VERSION 5.8 ;
BUSBITCHARS "[]" ;
DIVIDERCHAR "/" ;
UNITS
    DATABASE MICRONS 1000 ;
END UNITS

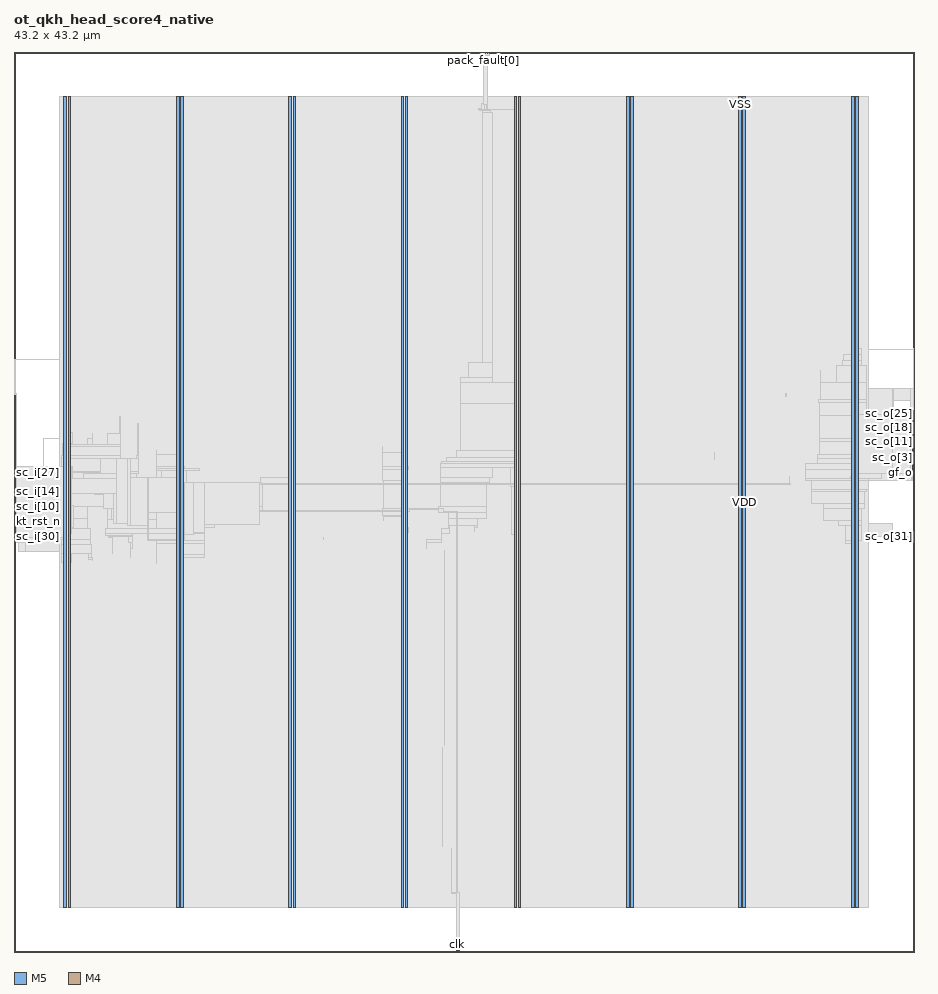
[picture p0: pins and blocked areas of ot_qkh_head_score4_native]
MACRO ot_qkh_head_score4_native
  FOREIGN ot_qkh_head_score4_native 0 0 ;
  CLASS BLOCK ;
  SIZE 43.2 BY 43.2 ;
  PIN clk
    DIRECTION INPUT ;
    USE SIGNAL ;
    PORT
      LAYER M5 ;
        RECT  21.264 0 21.288 0.084 ;
    END
  END clk
  PIN gf_i
    DIRECTION INPUT ;
    USE SIGNAL ;
    PORT
      LAYER M4 ;
        RECT  0 20.208 0.084 20.232 ;
    END
  END gf_i
  PIN gf_o
    DIRECTION OUTPUT ;
    USE SIGNAL ;
    PORT
      LAYER M4 ;
        RECT  43.116 22.992 43.2 23.016 ;
    END
  END gf_o
  PIN kt_rst_n
    DIRECTION OUTPUT ;
    USE SIGNAL ;
    PORT
      LAYER M4 ;
        RECT  0 20.304 0.084 20.328 ;
    END
  END kt_rst_n
  PIN pack_fault[0]
    DIRECTION INPUT ;
    USE SIGNAL ;
    PORT
      LAYER M5 ;
        RECT  22.512 43.116 22.536 43.2 ;
    END
  END pack_fault[0]
  PIN pack_fault[1]
    DIRECTION INPUT ;
    USE SIGNAL ;
    PORT
      LAYER M5 ;
        RECT  22.608 43.116 22.632 43.2 ;
    END
  END pack_fault[1]
  PIN pack_fault[2]
    DIRECTION INPUT ;
    USE SIGNAL ;
    PORT
      LAYER M5 ;
        RECT  22.704 43.116 22.728 43.2 ;
    END
  END pack_fault[2]
  PIN pack_fault[3]
    DIRECTION INPUT ;
    USE SIGNAL ;
    PORT
      LAYER M5 ;
        RECT  22.8 43.116 22.824 43.2 ;
    END
  END pack_fault[3]
  PIN rst_n
    DIRECTION INPUT ;
    USE SIGNAL ;
    PORT
      LAYER M5 ;
        RECT  21.36 0 21.384 0.084 ;
    END
  END rst_n
  PIN sc_i[0]
    DIRECTION INPUT ;
    USE SIGNAL ;
    PORT
      LAYER M4 ;
        RECT  0 20.4 0.084 20.424 ;
    END
  END sc_i[0]
  PIN sc_i[10]
    DIRECTION INPUT ;
    USE SIGNAL ;
    PORT
      LAYER M4 ;
        RECT  0 21.36 0.084 21.384 ;
    END
  END sc_i[10]
  PIN sc_i[11]
    DIRECTION INPUT ;
    USE SIGNAL ;
    PORT
      LAYER M4 ;
        RECT  0 21.456 0.084 21.48 ;
    END
  END sc_i[11]
  PIN sc_i[12]
    DIRECTION INPUT ;
    USE SIGNAL ;
    PORT
      LAYER M4 ;
        RECT  0 21.552 0.084 21.576 ;
    END
  END sc_i[12]
  PIN sc_i[13]
    DIRECTION INPUT ;
    USE SIGNAL ;
    PORT
      LAYER M4 ;
        RECT  0 21.648 0.084 21.672 ;
    END
  END sc_i[13]
  PIN sc_i[14]
    DIRECTION INPUT ;
    USE SIGNAL ;
    PORT
      LAYER M4 ;
        RECT  0 21.744 0.084 21.768 ;
    END
  END sc_i[14]
  PIN sc_i[15]
    DIRECTION INPUT ;
    USE SIGNAL ;
    PORT
      LAYER M4 ;
        RECT  0 21.84 0.084 21.864 ;
    END
  END sc_i[15]
  PIN sc_i[16]
    DIRECTION INPUT ;
    USE SIGNAL ;
    PORT
      LAYER M4 ;
        RECT  0 21.936 0.084 21.96 ;
    END
  END sc_i[16]
  PIN sc_i[17]
    DIRECTION INPUT ;
    USE SIGNAL ;
    PORT
      LAYER M4 ;
        RECT  0 22.032 0.084 22.056 ;
    END
  END sc_i[17]
  PIN sc_i[18]
    DIRECTION INPUT ;
    USE SIGNAL ;
    PORT
      LAYER M4 ;
        RECT  0 22.128 0.084 22.152 ;
    END
  END sc_i[18]
  PIN sc_i[19]
    DIRECTION INPUT ;
    USE SIGNAL ;
    PORT
      LAYER M4 ;
        RECT  0 22.224 0.084 22.248 ;
    END
  END sc_i[19]
  PIN sc_i[1]
    DIRECTION INPUT ;
    USE SIGNAL ;
    PORT
      LAYER M4 ;
        RECT  0 20.496 0.084 20.52 ;
    END
  END sc_i[1]
  PIN sc_i[20]
    DIRECTION INPUT ;
    USE SIGNAL ;
    PORT
      LAYER M4 ;
        RECT  0 22.32 0.084 22.344 ;
    END
  END sc_i[20]
  PIN sc_i[21]
    DIRECTION INPUT ;
    USE SIGNAL ;
    PORT
      LAYER M4 ;
        RECT  0 22.416 0.084 22.44 ;
    END
  END sc_i[21]
  PIN sc_i[22]
    DIRECTION INPUT ;
    USE SIGNAL ;
    PORT
      LAYER M4 ;
        RECT  0 22.512 0.084 22.536 ;
    END
  END sc_i[22]
  PIN sc_i[23]
    DIRECTION INPUT ;
    USE SIGNAL ;
    PORT
      LAYER M4 ;
        RECT  0 22.608 0.084 22.632 ;
    END
  END sc_i[23]
  PIN sc_i[24]
    DIRECTION INPUT ;
    USE SIGNAL ;
    PORT
      LAYER M4 ;
        RECT  0 22.704 0.084 22.728 ;
    END
  END sc_i[24]
  PIN sc_i[25]
    DIRECTION INPUT ;
    USE SIGNAL ;
    PORT
      LAYER M4 ;
        RECT  0 22.8 0.084 22.824 ;
    END
  END sc_i[25]
  PIN sc_i[26]
    DIRECTION INPUT ;
    USE SIGNAL ;
    PORT
      LAYER M4 ;
        RECT  0 22.896 0.084 22.92 ;
    END
  END sc_i[26]
  PIN sc_i[27]
    DIRECTION INPUT ;
    USE SIGNAL ;
    PORT
      LAYER M4 ;
        RECT  0 22.992 0.084 23.016 ;
    END
  END sc_i[27]
  PIN sc_i[28]
    DIRECTION INPUT ;
    USE SIGNAL ;
    PORT
      LAYER M4 ;
        RECT  0 23.088 0.084 23.112 ;
    END
  END sc_i[28]
  PIN sc_i[29]
    DIRECTION INPUT ;
    USE SIGNAL ;
    PORT
      LAYER M4 ;
        RECT  0 23.184 0.084 23.208 ;
    END
  END sc_i[29]
  PIN sc_i[2]
    DIRECTION INPUT ;
    USE SIGNAL ;
    PORT
      LAYER M4 ;
        RECT  0 20.592 0.084 20.616 ;
    END
  END sc_i[2]
  PIN sc_i[30]
    DIRECTION INPUT ;
    USE SIGNAL ;
    PORT
      LAYER M4 ;
        RECT  0 19.92 0.084 19.944 ;
    END
  END sc_i[30]
  PIN sc_i[31]
    DIRECTION INPUT ;
    USE SIGNAL ;
    PORT
      LAYER M4 ;
        RECT  0 20.016 0.084 20.04 ;
    END
  END sc_i[31]
  PIN sc_i[3]
    DIRECTION INPUT ;
    USE SIGNAL ;
    PORT
      LAYER M4 ;
        RECT  0 20.688 0.084 20.712 ;
    END
  END sc_i[3]
  PIN sc_i[4]
    DIRECTION INPUT ;
    USE SIGNAL ;
    PORT
      LAYER M4 ;
        RECT  0 20.784 0.084 20.808 ;
    END
  END sc_i[4]
  PIN sc_i[5]
    DIRECTION INPUT ;
    USE SIGNAL ;
    PORT
      LAYER M4 ;
        RECT  0 20.88 0.084 20.904 ;
    END
  END sc_i[5]
  PIN sc_i[6]
    DIRECTION INPUT ;
    USE SIGNAL ;
    PORT
      LAYER M4 ;
        RECT  0 20.976 0.084 21 ;
    END
  END sc_i[6]
  PIN sc_i[7]
    DIRECTION INPUT ;
    USE SIGNAL ;
    PORT
      LAYER M4 ;
        RECT  0 21.072 0.084 21.096 ;
    END
  END sc_i[7]
  PIN sc_i[8]
    DIRECTION INPUT ;
    USE SIGNAL ;
    PORT
      LAYER M4 ;
        RECT  0 21.168 0.084 21.192 ;
    END
  END sc_i[8]
  PIN sc_i[9]
    DIRECTION INPUT ;
    USE SIGNAL ;
    PORT
      LAYER M4 ;
        RECT  0 21.264 0.084 21.288 ;
    END
  END sc_i[9]
  PIN sc_o[0]
    DIRECTION OUTPUT ;
    USE SIGNAL ;
    PORT
      LAYER M4 ;
        RECT  43.116 23.088 43.2 23.112 ;
    END
  END sc_o[0]
  PIN sc_o[10]
    DIRECTION OUTPUT ;
    USE SIGNAL ;
    PORT
      LAYER M4 ;
        RECT  43.116 24.048 43.2 24.072 ;
    END
  END sc_o[10]
  PIN sc_o[11]
    DIRECTION OUTPUT ;
    USE SIGNAL ;
    PORT
      LAYER M4 ;
        RECT  43.116 24.144 43.2 24.168 ;
    END
  END sc_o[11]
  PIN sc_o[12]
    DIRECTION OUTPUT ;
    USE SIGNAL ;
    PORT
      LAYER M4 ;
        RECT  43.116 24.24 43.2 24.264 ;
    END
  END sc_o[12]
  PIN sc_o[13]
    DIRECTION OUTPUT ;
    USE SIGNAL ;
    PORT
      LAYER M4 ;
        RECT  43.116 24.336 43.2 24.36 ;
    END
  END sc_o[13]
  PIN sc_o[14]
    DIRECTION OUTPUT ;
    USE SIGNAL ;
    PORT
      LAYER M4 ;
        RECT  43.116 24.432 43.2 24.456 ;
    END
  END sc_o[14]
  PIN sc_o[15]
    DIRECTION OUTPUT ;
    USE SIGNAL ;
    PORT
      LAYER M4 ;
        RECT  43.116 24.528 43.2 24.552 ;
    END
  END sc_o[15]
  PIN sc_o[16]
    DIRECTION OUTPUT ;
    USE SIGNAL ;
    PORT
      LAYER M4 ;
        RECT  43.116 24.624 43.2 24.648 ;
    END
  END sc_o[16]
  PIN sc_o[17]
    DIRECTION OUTPUT ;
    USE SIGNAL ;
    PORT
      LAYER M4 ;
        RECT  43.116 24.72 43.2 24.744 ;
    END
  END sc_o[17]
  PIN sc_o[18]
    DIRECTION OUTPUT ;
    USE SIGNAL ;
    PORT
      LAYER M4 ;
        RECT  43.116 24.816 43.2 24.84 ;
    END
  END sc_o[18]
  PIN sc_o[19]
    DIRECTION OUTPUT ;
    USE SIGNAL ;
    PORT
      LAYER M4 ;
        RECT  43.116 24.912 43.2 24.936 ;
    END
  END sc_o[19]
  PIN sc_o[1]
    DIRECTION OUTPUT ;
    USE SIGNAL ;
    PORT
      LAYER M4 ;
        RECT  43.116 23.184 43.2 23.208 ;
    END
  END sc_o[1]
  PIN sc_o[20]
    DIRECTION OUTPUT ;
    USE SIGNAL ;
    PORT
      LAYER M4 ;
        RECT  43.116 25.008 43.2 25.032 ;
    END
  END sc_o[20]
  PIN sc_o[21]
    DIRECTION OUTPUT ;
    USE SIGNAL ;
    PORT
      LAYER M4 ;
        RECT  43.116 25.104 43.2 25.128 ;
    END
  END sc_o[21]
  PIN sc_o[22]
    DIRECTION OUTPUT ;
    USE SIGNAL ;
    PORT
      LAYER M4 ;
        RECT  43.116 25.2 43.2 25.224 ;
    END
  END sc_o[22]
  PIN sc_o[23]
    DIRECTION OUTPUT ;
    USE SIGNAL ;
    PORT
      LAYER M4 ;
        RECT  43.116 25.296 43.2 25.32 ;
    END
  END sc_o[23]
  PIN sc_o[24]
    DIRECTION OUTPUT ;
    USE SIGNAL ;
    PORT
      LAYER M4 ;
        RECT  43.116 25.392 43.2 25.416 ;
    END
  END sc_o[24]
  PIN sc_o[25]
    DIRECTION OUTPUT ;
    USE SIGNAL ;
    PORT
      LAYER M4 ;
        RECT  43.116 25.488 43.2 25.512 ;
    END
  END sc_o[25]
  PIN sc_o[26]
    DIRECTION OUTPUT ;
    USE SIGNAL ;
    PORT
      LAYER M4 ;
        RECT  43.116 25.584 43.2 25.608 ;
    END
  END sc_o[26]
  PIN sc_o[27]
    DIRECTION OUTPUT ;
    USE SIGNAL ;
    PORT
      LAYER M4 ;
        RECT  43.116 25.68 43.2 25.704 ;
    END
  END sc_o[27]
  PIN sc_o[28]
    DIRECTION OUTPUT ;
    USE SIGNAL ;
    PORT
      LAYER M4 ;
        RECT  43.116 25.776 43.2 25.8 ;
    END
  END sc_o[28]
  PIN sc_o[29]
    DIRECTION OUTPUT ;
    USE SIGNAL ;
    PORT
      LAYER M4 ;
        RECT  43.116 25.872 43.2 25.896 ;
    END
  END sc_o[29]
  PIN sc_o[2]
    DIRECTION OUTPUT ;
    USE SIGNAL ;
    PORT
      LAYER M4 ;
        RECT  43.116 23.28 43.2 23.304 ;
    END
  END sc_o[2]
  PIN sc_o[30]
    DIRECTION OUTPUT ;
    USE SIGNAL ;
    PORT
      LAYER M4 ;
        RECT  43.116 25.968 43.2 25.992 ;
    END
  END sc_o[30]
  PIN sc_o[31]
    DIRECTION OUTPUT ;
    USE SIGNAL ;
    PORT
      LAYER M4 ;
        RECT  43.116 19.92 43.2 19.944 ;
    END
  END sc_o[31]
  PIN sc_o[3]
    DIRECTION OUTPUT ;
    USE SIGNAL ;
    PORT
      LAYER M4 ;
        RECT  43.116 23.376 43.2 23.4 ;
    END
  END sc_o[3]
  PIN sc_o[4]
    DIRECTION OUTPUT ;
    USE SIGNAL ;
    PORT
      LAYER M4 ;
        RECT  43.116 23.472 43.2 23.496 ;
    END
  END sc_o[4]
  PIN sc_o[5]
    DIRECTION OUTPUT ;
    USE SIGNAL ;
    PORT
      LAYER M4 ;
        RECT  43.116 23.568 43.2 23.592 ;
    END
  END sc_o[5]
  PIN sc_o[6]
    DIRECTION OUTPUT ;
    USE SIGNAL ;
    PORT
      LAYER M4 ;
        RECT  43.116 23.664 43.2 23.688 ;
    END
  END sc_o[6]
  PIN sc_o[7]
    DIRECTION OUTPUT ;
    USE SIGNAL ;
    PORT
      LAYER M4 ;
        RECT  43.116 23.76 43.2 23.784 ;
    END
  END sc_o[7]
  PIN sc_o[8]
    DIRECTION OUTPUT ;
    USE SIGNAL ;
    PORT
      LAYER M4 ;
        RECT  43.116 23.856 43.2 23.88 ;
    END
  END sc_o[8]
  PIN sc_o[9]
    DIRECTION OUTPUT ;
    USE SIGNAL ;
    PORT
      LAYER M4 ;
        RECT  43.116 23.952 43.2 23.976 ;
    END
  END sc_o[9]
  PIN sf_i
    DIRECTION INPUT ;
    USE SIGNAL ;
    PORT
      LAYER M4 ;
        RECT  0 20.112 0.084 20.136 ;
    END
  END sf_i
  PIN sf_o
    DIRECTION OUTPUT ;
    USE SIGNAL ;
    PORT
      LAYER M4 ;
        RECT  43.116 20.016 43.2 20.04 ;
    END
  END sf_o
  PIN VDD
    DIRECTION INOUT ;
    USE POWER ;
    PORT
      LAYER M5 ;
        RECT  40.392 2.151 40.512 41.049 ;
        RECT  34.992 2.151 35.112 41.049 ;
        RECT  29.592 2.151 29.712 41.049 ;
        RECT  24.192 2.151 24.312 41.049 ;
        RECT  18.792 2.151 18.912 41.049 ;
        RECT  13.392 2.151 13.512 41.049 ;
        RECT  7.992 2.151 8.112 41.049 ;
        RECT  2.592 2.151 2.712 41.049 ;
    END
  END VDD
  PIN VSS
    DIRECTION INOUT ;
    USE GROUND ;
    PORT
      LAYER M5 ;
        RECT  40.2 2.137 40.32 41.063 ;
        RECT  34.8 2.137 34.92 41.063 ;
        RECT  29.4 2.137 29.52 41.063 ;
        RECT  24 2.137 24.12 41.063 ;
        RECT  18.6 2.137 18.72 41.063 ;
        RECT  13.2 2.137 13.32 41.063 ;
        RECT  7.8 2.137 7.92 41.063 ;
        RECT  2.4 2.137 2.52 41.063 ;
    END
  END VSS
  # OT_OBS_CLOSED layer=M5 d_um=1.536 added=1
  OBS
    LAYER RVTN ;
     RECT  2.16 2.16 41.04 2.295 ;
     RECT  2.16 2.565 41.04 2.835 ;
     RECT  2.16 3.105 41.04 3.375 ;
     RECT  2.16 3.645 41.04 3.915 ;
     RECT  2.16 4.185 41.04 4.455 ;
     RECT  2.16 4.725 41.04 4.995 ;
     RECT  2.16 5.265 41.04 5.535 ;
     RECT  2.16 5.805 41.04 6.075 ;
     RECT  2.16 6.345 41.04 6.615 ;
     RECT  2.16 6.885 41.04 7.155 ;
     RECT  2.16 7.425 41.04 7.695 ;
     RECT  2.16 7.965 41.04 8.235 ;
     RECT  2.16 8.505 41.04 8.775 ;
     RECT  2.16 9.045 41.04 9.315 ;
     RECT  2.16 9.585 41.04 9.855 ;
     RECT  2.16 10.125 41.04 10.395 ;
     RECT  2.16 10.665 41.04 10.935 ;
     RECT  2.16 11.205 41.04 11.475 ;
     RECT  2.16 11.745 41.04 12.015 ;
     RECT  2.16 12.285 41.04 12.555 ;
     RECT  2.16 12.825 41.04 13.095 ;
     RECT  2.16 13.365 41.04 13.635 ;
     RECT  2.16 13.905 41.04 14.175 ;
     RECT  2.16 14.445 41.04 14.715 ;
     RECT  2.16 14.985 41.04 15.255 ;
     RECT  2.16 15.525 41.04 15.795 ;
     RECT  2.16 16.065 41.04 16.335 ;
     RECT  2.16 16.605 41.04 16.875 ;
     RECT  2.16 17.145 41.04 17.415 ;
     RECT  2.16 17.685 41.04 17.955 ;
     RECT  2.16 18.225 41.04 18.495 ;
     RECT  2.16 18.765 41.04 19.035 ;
     RECT  2.16 19.305 41.04 19.575 ;
     RECT  2.16 19.845 41.04 20.115 ;
     RECT  2.16 20.385 41.04 20.655 ;
     RECT  2.16 20.925 41.04 21.195 ;
     RECT  2.16 21.465 41.04 21.735 ;
     RECT  2.16 22.005 41.04 22.275 ;
     RECT  2.16 22.545 41.04 22.815 ;
     RECT  2.16 23.085 41.04 23.355 ;
     RECT  2.16 23.625 41.04 23.895 ;
     RECT  2.16 24.165 41.04 24.435 ;
     RECT  2.16 24.705 41.04 24.975 ;
     RECT  2.16 25.245 41.04 25.515 ;
     RECT  2.16 25.785 41.04 26.055 ;
     RECT  2.16 26.325 41.04 26.595 ;
     RECT  2.16 26.865 41.04 27.135 ;
     RECT  2.16 27.405 41.04 27.675 ;
     RECT  2.16 27.945 41.04 28.215 ;
     RECT  2.16 28.485 41.04 28.755 ;
     RECT  2.16 29.025 41.04 29.295 ;
     RECT  2.16 29.565 41.04 29.835 ;
     RECT  2.16 30.105 41.04 30.375 ;
     RECT  2.16 30.645 41.04 30.915 ;
     RECT  2.16 31.185 41.04 31.455 ;
     RECT  2.16 31.725 41.04 31.995 ;
     RECT  2.16 32.265 41.04 32.535 ;
     RECT  2.16 32.805 41.04 33.075 ;
     RECT  2.16 33.345 41.04 33.615 ;
     RECT  2.16 33.885 41.04 34.155 ;
     RECT  2.16 34.425 41.04 34.695 ;
     RECT  2.16 34.965 41.04 35.235 ;
     RECT  2.16 35.505 41.04 35.775 ;
     RECT  2.16 36.045 41.04 36.315 ;
     RECT  2.16 36.585 41.04 36.855 ;
     RECT  2.16 37.125 41.04 37.395 ;
     RECT  2.16 37.665 41.04 37.935 ;
     RECT  2.16 38.205 41.04 38.475 ;
     RECT  2.16 38.745 41.04 39.015 ;
     RECT  2.16 39.285 41.04 39.555 ;
     RECT  2.16 39.825 41.04 40.095 ;
     RECT  2.16 40.365 41.04 40.635 ;
     RECT  2.16 40.905 41.04 41.04 ;
    LAYER RVTP ;
     RECT  2.16 2.295 41.04 2.565 ;
     RECT  2.16 2.835 41.04 3.105 ;
     RECT  2.16 3.375 41.04 3.645 ;
     RECT  2.16 3.915 41.04 4.185 ;
     RECT  2.16 4.455 41.04 4.725 ;
     RECT  2.16 4.995 41.04 5.265 ;
     RECT  2.16 5.535 41.04 5.805 ;
     RECT  2.16 6.075 41.04 6.345 ;
     RECT  2.16 6.615 41.04 6.885 ;
     RECT  2.16 7.155 41.04 7.425 ;
     RECT  2.16 7.695 41.04 7.965 ;
     RECT  2.16 8.235 41.04 8.505 ;
     RECT  2.16 8.775 41.04 9.045 ;
     RECT  2.16 9.315 41.04 9.585 ;
     RECT  2.16 9.855 41.04 10.125 ;
     RECT  2.16 10.395 41.04 10.665 ;
     RECT  2.16 10.935 41.04 11.205 ;
     RECT  2.16 11.475 41.04 11.745 ;
     RECT  2.16 12.015 41.04 12.285 ;
     RECT  2.16 12.555 41.04 12.825 ;
     RECT  2.16 13.095 41.04 13.365 ;
     RECT  2.16 13.635 41.04 13.905 ;
     RECT  2.16 14.175 41.04 14.445 ;
     RECT  2.16 14.715 41.04 14.985 ;
     RECT  2.16 15.255 41.04 15.525 ;
     RECT  2.16 15.795 41.04 16.065 ;
     RECT  2.16 16.335 41.04 16.605 ;
     RECT  2.16 16.875 41.04 17.145 ;
     RECT  2.16 17.415 41.04 17.685 ;
     RECT  2.16 17.955 41.04 18.225 ;
     RECT  2.16 18.495 41.04 18.765 ;
     RECT  2.16 19.035 41.04 19.305 ;
     RECT  2.16 19.575 41.04 19.845 ;
     RECT  2.16 20.115 41.04 20.385 ;
     RECT  2.16 20.655 41.04 20.925 ;
     RECT  2.16 21.195 41.04 21.465 ;
     RECT  2.16 21.735 41.04 22.005 ;
     RECT  2.16 22.275 41.04 22.545 ;
     RECT  2.16 22.815 41.04 23.085 ;
     RECT  2.16 23.355 41.04 23.625 ;
     RECT  2.16 23.895 41.04 24.165 ;
     RECT  2.16 24.435 41.04 24.705 ;
     RECT  2.16 24.975 41.04 25.245 ;
     RECT  2.16 25.515 41.04 25.785 ;
     RECT  2.16 26.055 41.04 26.325 ;
     RECT  2.16 26.595 41.04 26.865 ;
     RECT  2.16 27.135 41.04 27.405 ;
     RECT  2.16 27.675 41.04 27.945 ;
     RECT  2.16 28.215 41.04 28.485 ;
     RECT  2.16 28.755 41.04 29.025 ;
     RECT  2.16 29.295 41.04 29.565 ;
     RECT  2.16 29.835 41.04 30.105 ;
     RECT  2.16 30.375 41.04 30.645 ;
     RECT  2.16 30.915 41.04 31.185 ;
     RECT  2.16 31.455 41.04 31.725 ;
     RECT  2.16 31.995 41.04 32.265 ;
     RECT  2.16 32.535 41.04 32.805 ;
     RECT  2.16 33.075 41.04 33.345 ;
     RECT  2.16 33.615 41.04 33.885 ;
     RECT  2.16 34.155 41.04 34.425 ;
     RECT  2.16 34.695 41.04 34.965 ;
     RECT  2.16 35.235 41.04 35.505 ;
     RECT  2.16 35.775 41.04 36.045 ;
     RECT  2.16 36.315 41.04 36.585 ;
     RECT  2.16 36.855 41.04 37.125 ;
     RECT  2.16 37.395 41.04 37.665 ;
     RECT  2.16 37.935 41.04 38.205 ;
     RECT  2.16 38.475 41.04 38.745 ;
     RECT  2.16 39.015 41.04 39.285 ;
     RECT  2.16 39.555 41.04 39.825 ;
     RECT  2.16 40.095 41.04 40.365 ;
     RECT  2.16 40.635 41.04 40.905 ;
    LAYER M1 ;
     RECT  2.16 2.151 41.04 41.049 ;
    LAYER M2 ;
     RECT  0.031 26.766 0.131 26.784 ;
     RECT  0.139 19.656 0.211 19.674 ;
     RECT  0.175 21.402 0.211 21.42 ;
     RECT  0.211 19.242 0.535 19.674 ;
     RECT  0.535 19.242 2.16 19.908 ;
     RECT  0.211 20.7 2.16 21.42 ;
     RECT  0.211 22.752 2.16 22.77 ;
     RECT  1.399 24.642 2.16 24.66 ;
     RECT  0.031 28.422 2.16 28.44 ;
     RECT  2.16 2.151 41.04 41.049 ;
     RECT  41.04 19.926 42.179 20.574 ;
     RECT  41.04 22.626 42.179 27.054 ;
     RECT  42.179 22.626 42.215 23.544 ;
     RECT  42.179 26.136 42.215 27.054 ;
     RECT  42.215 26.496 43.079 27.054 ;
     RECT  42.179 19.926 43.115 19.944 ;
     RECT  42.215 22.626 43.115 23.346 ;
     RECT  43.079 26.496 43.115 26.514 ;
     RECT  41.04 28.926 43.187 28.944 ;
    LAYER M3 ;
     RECT  2.415 2.143 2.505 2.413 ;
     RECT  7.815 2.143 7.905 2.413 ;
     RECT  13.215 2.143 13.305 2.413 ;
     RECT  18.615 2.143 18.705 2.413 ;
     RECT  24.015 2.143 24.105 2.413 ;
     RECT  29.415 2.143 29.505 2.413 ;
     RECT  34.815 2.143 34.905 2.413 ;
     RECT  40.215 2.143 40.305 2.413 ;
     RECT  20.988 2.827 21.006 4.955 ;
     RECT  20.556 5.071 20.574 9.815 ;
     RECT  2.415 2.413 2.697 18.661 ;
     RECT  2.376 18.661 2.697 18.697 ;
     RECT  3.744 18.769 3.762 18.841 ;
     RECT  7.815 2.413 8.097 18.931 ;
     RECT  3.564 18.841 3.762 18.959 ;
     RECT  7.815 18.931 9.126 19.075 ;
     RECT  2.304 18.697 2.754 19.111 ;
     RECT  3.564 18.959 3.726 19.111 ;
     RECT  20.664 9.931 20.682 19.265 ;
     RECT  5.58 18.931 5.598 19.345 ;
     RECT  2.304 19.111 3.726 19.571 ;
     RECT  6.84 18.661 6.858 19.615 ;
     RECT  7.812 19.075 9.126 19.615 ;
     RECT  40.215 2.413 40.497 19.615 ;
     RECT  0.216 19.237 0.234 19.651 ;
     RECT  5.58 19.345 5.67 19.651 ;
     RECT  19.8 19.381 19.818 19.651 ;
     RECT  39.924 19.615 40.497 19.741 ;
     RECT  6.84 19.615 9.126 19.771 ;
     RECT  2.304 19.571 3.654 19.777 ;
     RECT  19.8 19.651 20.538 19.805 ;
     RECT  14.832 19.777 14.85 19.877 ;
     RECT  0.144 19.651 0.234 19.885 ;
     RECT  4.716 19.111 4.734 19.885 ;
     RECT  4.536 19.885 4.734 19.921 ;
     RECT  5.508 19.651 5.67 19.921 ;
     RECT  4.536 19.921 5.67 20.011 ;
     RECT  43.092 19.921 43.11 20.045 ;
     RECT  24.015 2.413 24.297 20.047 ;
     RECT  4.392 20.011 5.67 20.083 ;
     RECT  6.408 19.771 9.126 20.083 ;
     RECT  20.52 19.805 20.538 20.083 ;
     RECT  18.615 2.413 18.897 20.119 ;
     RECT  0.144 19.885 0.558 20.203 ;
     RECT  2.232 19.777 3.654 20.309 ;
     RECT  4.392 20.083 9.126 20.309 ;
     RECT  20.52 20.083 20.898 20.309 ;
     RECT  4.464 20.309 9.126 20.345 ;
     RECT  18.615 20.119 18.954 20.381 ;
     RECT  7.815 20.345 9.126 20.389 ;
     RECT  22.104 20.191 22.122 20.389 ;
     RECT  20.88 20.309 20.898 20.461 ;
     RECT  22.104 20.389 22.266 20.461 ;
     RECT  39.924 19.741 40.698 20.461 ;
     RECT  7.815 20.389 9.63 20.579 ;
     RECT  42.156 19.915 42.174 20.579 ;
     RECT  7.815 20.579 9.558 20.615 ;
     RECT  0.108 20.203 0.558 20.621 ;
     RECT  39.564 20.461 40.698 20.731 ;
     RECT  4.464 20.345 6.858 20.759 ;
     RECT  2.232 20.309 3.546 20.813 ;
     RECT  20.88 20.461 22.266 20.821 ;
     RECT  10.836 20.821 10.854 20.857 ;
     RECT  11.736 20.539 11.754 20.857 ;
     RECT  17.712 20.731 17.73 20.893 ;
     RECT  18.615 20.381 18.897 20.893 ;
     RECT  17.712 20.893 18.897 20.929 ;
     RECT  9.216 20.615 9.234 21.029 ;
     RECT  5.472 20.759 6.858 21.115 ;
     RECT  20.88 20.821 22.698 21.115 ;
     RECT  7.815 20.615 8.262 21.149 ;
     RECT  10.836 20.857 11.754 21.163 ;
     RECT  17.676 20.929 18.897 21.163 ;
     RECT  38.844 20.731 40.698 21.271 ;
     RECT  17.676 21.163 18.99 21.293 ;
     RECT  17.676 21.293 18.897 21.299 ;
     RECT  4.464 20.759 4.698 21.307 ;
     RECT  2.304 20.813 3.546 21.361 ;
     RECT  4.32 21.307 4.698 21.361 ;
     RECT  10.836 21.163 11.934 21.361 ;
     RECT  10.764 21.361 11.934 21.389 ;
     RECT  20.376 21.115 22.698 21.389 ;
     RECT  10.764 21.389 10.782 21.461 ;
     RECT  38.844 21.271 40.842 21.505 ;
     RECT  34.815 2.413 35.097 21.541 ;
     RECT  5.472 21.115 7.074 21.695 ;
     RECT  0.108 20.621 0.234 21.869 ;
     RECT  5.472 21.695 5.922 21.929 ;
     RECT  6.696 21.695 7.074 21.979 ;
     RECT  7.815 21.149 8.154 21.979 ;
     RECT  2.304 21.361 4.698 22.009 ;
     RECT  5.472 21.929 5.778 22.009 ;
     RECT  38.268 21.505 40.842 22.081 ;
     RECT  6.696 21.979 8.154 22.199 ;
     RECT  38.268 22.081 40.914 22.207 ;
     RECT  23.904 20.047 24.297 22.351 ;
     RECT  11.736 21.389 11.934 22.459 ;
     RECT  13.215 2.413 13.497 22.459 ;
     RECT  11.736 22.459 13.497 22.505 ;
     RECT  7.815 22.199 8.154 22.507 ;
     RECT  7.815 22.507 8.19 22.549 ;
     RECT  20.484 21.389 22.698 22.549 ;
     RECT  34.776 21.541 35.097 22.577 ;
     RECT  0.108 21.869 0.126 22.603 ;
     RECT  6.696 22.199 7.074 22.621 ;
     RECT  17.712 21.299 18.897 22.621 ;
     RECT  38.268 22.207 41.022 22.621 ;
     RECT  2.304 22.009 5.778 22.711 ;
     RECT  37.98 22.621 41.022 22.711 ;
     RECT  6.66 22.621 7.074 22.739 ;
     RECT  0.108 22.603 0.162 22.747 ;
     RECT  11.844 22.505 13.497 22.775 ;
     RECT  6.768 22.739 7.074 22.781 ;
     RECT  20.484 22.549 22.842 22.783 ;
     RECT  37.224 22.459 37.242 22.811 ;
     RECT  0.108 22.747 0.234 22.829 ;
     RECT  2.304 22.711 5.886 22.981 ;
     RECT  2.304 22.981 5.958 22.987 ;
     RECT  2.268 22.987 5.958 23.045 ;
     RECT  7.815 22.549 8.298 23.089 ;
     RECT  6.84 22.781 7.074 23.125 ;
     RECT  7.815 23.089 8.91 23.125 ;
     RECT  17.676 22.621 18.897 23.161 ;
     RECT  37.98 22.711 41.634 23.161 ;
     RECT  6.84 23.125 8.91 23.189 ;
     RECT  20.484 22.783 22.986 23.251 ;
     RECT  23.832 22.351 24.297 23.251 ;
     RECT  0.108 22.829 0.162 23.309 ;
     RECT  6.84 23.189 8.19 23.315 ;
     RECT  17.676 23.161 18.918 23.315 ;
     RECT  20.484 23.251 24.297 23.459 ;
     RECT  37.98 23.161 42.21 23.459 ;
     RECT  20.52 23.459 24.297 23.549 ;
     RECT  34.815 22.577 35.097 23.593 ;
     RECT  2.304 23.045 5.958 23.693 ;
     RECT  38.556 23.459 42.21 23.693 ;
     RECT  20.772 23.549 24.297 23.729 ;
     RECT  43.092 22.621 43.11 23.789 ;
     RECT  5.868 23.693 5.958 23.819 ;
     RECT  2.304 23.693 5.13 23.855 ;
     RECT  6.84 23.315 8.097 23.891 ;
     RECT  38.556 23.693 40.698 23.891 ;
     RECT  34.776 23.593 35.097 23.927 ;
     RECT  41.544 23.693 42.21 23.981 ;
     RECT  17.676 23.315 18.897 23.999 ;
     RECT  33.624 23.629 33.642 23.999 ;
     RECT  6.84 23.891 6.858 24.089 ;
     RECT  21.24 23.729 24.297 24.089 ;
     RECT  41.544 23.981 42.174 24.173 ;
     RECT  2.34 23.855 5.13 24.269 ;
     RECT  17.676 23.999 17.694 24.269 ;
     RECT  2.34 24.269 5.094 24.359 ;
     RECT  2.34 24.359 2.79 24.395 ;
     RECT  38.664 23.891 40.698 24.523 ;
     RECT  3.528 24.359 3.762 24.629 ;
     RECT  1.404 22.507 1.422 24.665 ;
     RECT  38.664 24.523 40.842 24.665 ;
     RECT  3.744 24.629 3.762 24.899 ;
     RECT  4.5 24.359 5.094 24.899 ;
     RECT  34.815 23.927 35.097 24.907 ;
     RECT  2.415 24.395 2.79 24.935 ;
     RECT  5.904 23.819 5.958 25.169 ;
     RECT  41.58 24.173 42.174 25.169 ;
     RECT  5.94 25.169 5.958 25.349 ;
     RECT  41.796 25.169 42.174 25.349 ;
     RECT  43.092 25.195 43.11 25.387 ;
     RECT  34.776 24.907 35.097 25.439 ;
     RECT  41.832 25.349 42.174 25.619 ;
     RECT  42.12 25.619 42.174 25.675 ;
     RECT  5.076 24.899 5.094 25.709 ;
     RECT  38.664 24.665 40.734 25.771 ;
     RECT  43.056 25.387 43.11 25.963 ;
     RECT  42.12 25.675 42.21 25.979 ;
     RECT  43.02 25.963 43.11 26.059 ;
     RECT  43.02 26.059 43.182 26.093 ;
     RECT  42.156 25.979 42.21 26.159 ;
     RECT  42.156 26.159 42.174 26.249 ;
     RECT  21.42 24.089 24.297 26.321 ;
     RECT  38.664 25.771 40.914 26.365 ;
     RECT  34.815 25.439 35.097 26.491 ;
     RECT  38.628 26.365 40.914 26.519 ;
     RECT  0.108 23.309 0.126 26.761 ;
     RECT  0.036 26.761 0.126 26.789 ;
     RECT  34.776 26.491 35.097 26.789 ;
     RECT  37.044 26.671 37.062 26.789 ;
     RECT  43.056 26.093 43.182 27.059 ;
     RECT  21.456 26.321 24.297 27.329 ;
     RECT  38.7 26.519 40.914 27.329 ;
     RECT  21.456 27.329 22.986 27.599 ;
     RECT  38.7 27.329 38.718 27.905 ;
     RECT  39.456 27.329 40.914 28.139 ;
     RECT  39.528 28.139 40.662 28.175 ;
     RECT  21.816 27.599 22.986 28.319 ;
     RECT  39.78 28.175 40.662 28.409 ;
     RECT  0.036 26.789 0.054 28.445 ;
     RECT  39.816 28.409 40.662 28.679 ;
     RECT  43.164 27.059 43.182 28.949 ;
     RECT  40.215 28.679 40.662 28.985 ;
     RECT  22.5 28.319 22.986 40.289 ;
     RECT  22.5 40.289 22.878 40.405 ;
     RECT  22.32 40.405 22.878 40.493 ;
     RECT  22.428 40.493 22.878 40.559 ;
     RECT  22.428 40.559 22.842 40.733 ;
     RECT  2.415 24.935 2.697 40.787 ;
     RECT  7.815 23.891 8.097 40.787 ;
     RECT  13.215 22.775 13.497 40.787 ;
     RECT  18.615 23.999 18.897 40.787 ;
     RECT  24.015 27.329 24.297 40.787 ;
     RECT  29.415 2.413 29.697 40.787 ;
     RECT  34.815 26.789 35.097 40.787 ;
     RECT  40.215 28.985 40.497 40.787 ;
     RECT  22.644 40.733 22.842 40.829 ;
     RECT  22.644 40.829 22.734 41.021 ;
     RECT  2.415 40.787 2.505 41.057 ;
     RECT  7.815 40.787 7.905 41.057 ;
     RECT  13.215 40.787 13.305 41.057 ;
     RECT  18.615 40.787 18.705 41.057 ;
     RECT  24.015 40.787 24.105 41.057 ;
     RECT  29.415 40.787 29.505 41.057 ;
     RECT  34.815 40.787 34.905 41.057 ;
     RECT  40.215 40.787 40.305 41.057 ;
     RECT  22.716 41.021 22.734 43.085 ;
    LAYER M4 ;
     RECT  0.06 19.92 0.133 23.208 ;
     RECT  0.133 19.92 2.408 23.304 ;
     RECT  2.408 2.148 2.512 41.052 ;
     RECT  2.512 2.418 2.704 40.782 ;
     RECT  2.704 20.112 2.765 23.304 ;
     RECT  2.765 22.752 2.801 23.304 ;
     RECT  2.765 20.4 2.837 21.432 ;
     RECT  2.837 21.408 2.873 21.432 ;
     RECT  2.801 22.752 3.341 23.016 ;
     RECT  3.341 22.992 4.129 23.016 ;
     RECT  3.877 21.984 4.309 22.008 ;
     RECT  4.309 21.312 4.777 22.008 ;
     RECT  4.777 20.592 4.921 22.008 ;
     RECT  4.129 22.992 4.921 23.688 ;
     RECT  4.921 20.592 5.425 23.688 ;
     RECT  5.425 20.496 5.609 23.688 ;
     RECT  5.609 20.496 6.397 22.776 ;
     RECT  6.397 19.776 6.437 22.776 ;
     RECT  6.437 19.776 7.808 19.8 ;
     RECT  6.437 21.12 7.808 22.776 ;
     RECT  7.808 2.148 7.912 41.052 ;
     RECT  7.912 2.418 8.104 40.782 ;
     RECT  8.104 19.776 8.165 22.536 ;
     RECT  8.165 20.064 8.597 22.536 ;
     RECT  8.597 20.16 9.137 22.536 ;
     RECT  9.137 20.544 11.765 22.536 ;
     RECT  11.765 22.464 11.873 22.536 ;
     RECT  11.765 21.168 13.208 21.192 ;
     RECT  11.873 22.464 13.208 22.488 ;
     RECT  13.208 2.148 13.312 41.052 ;
     RECT  13.312 2.418 13.504 40.782 ;
     RECT  13.504 21.168 18.608 21.192 ;
     RECT  13.504 22.464 18.608 22.488 ;
     RECT  18.608 2.148 18.712 41.052 ;
     RECT  18.712 2.418 18.904 40.782 ;
     RECT  18.904 21.168 19.001 21.288 ;
     RECT  19.001 21.264 20.365 21.288 ;
     RECT  20.365 21.12 20.621 21.288 ;
     RECT  20.621 21.12 21.299 21.144 ;
     RECT  20.977 2.832 21.395 2.856 ;
     RECT  22.309 40.464 22.417 40.488 ;
     RECT  22.417 40.464 22.589 40.728 ;
     RECT  22.589 40.464 22.673 41.016 ;
     RECT  22.673 40.464 22.739 40.488 ;
     RECT  22.705 43.056 22.835 43.08 ;
     RECT  18.904 22.464 24.008 22.488 ;
     RECT  24.008 2.148 24.112 41.052 ;
     RECT  24.112 2.418 24.304 40.782 ;
     RECT  24.304 22.464 29.408 22.488 ;
     RECT  29.408 2.148 29.512 41.052 ;
     RECT  29.512 2.418 29.704 40.782 ;
     RECT  29.704 22.464 34.808 22.488 ;
     RECT  34.808 2.148 34.912 41.052 ;
     RECT  34.912 2.418 35.104 40.782 ;
     RECT  35.104 22.464 37.253 22.488 ;
     RECT  40.129 22.8 40.201 22.824 ;
     RECT  40.201 22.8 40.208 23.112 ;
     RECT  40.208 2.148 40.312 41.052 ;
     RECT  40.312 2.418 40.504 40.782 ;
     RECT  40.504 22.992 42.145 25.8 ;
     RECT  42.145 22.992 43.009 25.896 ;
     RECT  42.145 19.92 43.081 19.944 ;
     RECT  43.081 19.92 43.164 20.04 ;
     RECT  43.009 22.992 43.164 26.088 ;
     RECT  43.164 26.064 43.193 26.088 ;
    LAYER M5 ;
     RECT  2.4 2.137 2.52 2.151 ;
     RECT  7.8 2.137 7.92 2.151 ;
     RECT  13.2 2.137 13.32 2.151 ;
     RECT  18.6 2.137 18.72 2.151 ;
     RECT  24 2.137 24.12 2.151 ;
     RECT  29.4 2.137 29.52 2.151 ;
     RECT  34.8 2.137 34.92 2.151 ;
     RECT  40.2 2.137 40.32 2.151 ;
     RECT  21.264 0.016 21.384 2.867 ;
     RECT  21.264 2.867 21.288 21.155 ;
     RECT  22.704 40.453 22.728 40.693 ;
     RECT  2.4 2.151 2.712 41.049 ;
     RECT  7.8 2.151 8.112 41.049 ;
     RECT  13.2 2.151 13.512 41.049 ;
     RECT  18.6 2.151 18.912 41.049 ;
     RECT  24 2.151 24.312 41.049 ;
     RECT  29.4 2.151 29.712 41.049 ;
     RECT  34.8 2.151 35.112 41.049 ;
     RECT  40.2 2.151 40.512 41.049 ;
     RECT  2.4 41.049 2.52 41.063 ;
     RECT  7.8 41.049 7.92 41.063 ;
     RECT  13.2 41.049 13.32 41.063 ;
     RECT  18.6 41.049 18.72 41.063 ;
     RECT  24 41.049 24.12 41.063 ;
     RECT  29.4 41.049 29.52 41.063 ;
     RECT  34.8 41.049 34.92 41.063 ;
     RECT  40.2 41.049 40.32 41.063 ;
     RECT  22.512 40.693 22.728 43.045 ;
     RECT  22.512 43.045 22.824 43.152 ;
     RECT  22.728 40.453 24 41.063 ;
  END
END ot_qkh_head_score4_native
END LIBRARY
